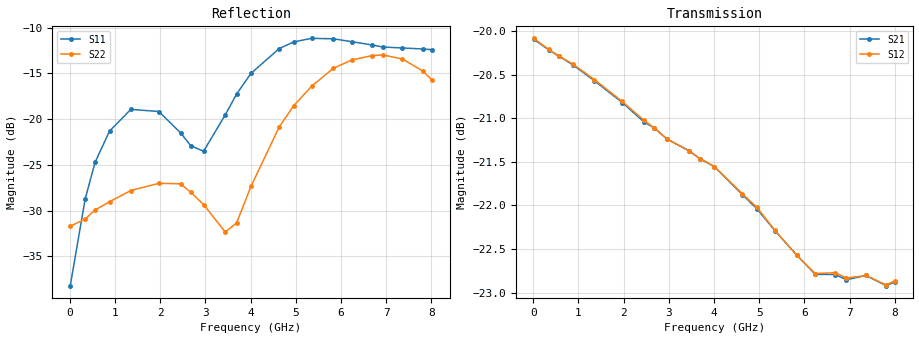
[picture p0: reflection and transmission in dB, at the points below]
!Agilent Technologies,E5071B,MY42404982,A.09.10
!Date: Mon Oct 20 13:36:23 2025
!Data & Calibration Information:
!Freq	S11:SOLT2(ON)	S21:SOLT2(ON)	S12:SOLT2(ON)	S22:SOLT2(ON)
# Hz S RI R 50
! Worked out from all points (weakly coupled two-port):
!   801 points, 10 MHz to 8.01 GHz, reference 50 ohm
!   highest |S21| = -20.09 dB at 10 MHz (marker M1); lowest = -22.9 dB at 7.81 GHz (marker M2)
!   lowest |S11| = -38.2 dB at 10 MHz (marker M3), VSWR 1.02, Z = 48.8 - j0.159 ohm
!   |S11| at or under -10 dB: start of sweep to end of sweep
!   |S22| runs from -32.4 to -13.0 dB; largest |S21 - S12| = 0.00077
!   S11 on the Smith chart (normalised r, x): 10 MHz: 0.98, -0.00; 4.63 GHz: 0.63, +0.13; 5.83 GHz: 1.18, +0.59; 6.93 GHz: 1.33, -0.49; 8.01 GHz: 0.63, -0.14
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1e7  -0.0122 -0.00163  0.0989 -0.00213  0.099 -0.00222  0.026 -0.000864
3.4e8  -0.0242 -0.0276  0.08 -0.0558  0.08 -0.0559  0.0225 -0.0174
5.6e8  -0.0433 -0.0389  0.0526 -0.0812  0.0525 -0.0813  0.0147 -0.0283
8.8e8  -0.0794 -0.0333  0.00115 -0.0956  0.00111 -0.0957  -0.0071 -0.0347
1.35e9  -0.1109 0.0218  -0.0678 -0.0646  -0.0679 -0.0647  -0.0368 -0.0175
1.97e9  -0.0507 0.0977  -0.0865 0.0282  -0.0866 0.0283  -0.0338 0.0291
2.45e9  0.0328 0.0775  -0.0372 0.0805  -0.0372 0.0807  -0.00152 0.0443
2.68e9  0.0594 0.0396  -0.00353 0.0879  -0.00349 0.0879  0.0146 0.037
2.96e9  0.0638 -0.0198  0.0366 0.0786  0.0366 0.0786  0.0267 0.0213
3.44e9  -0.00484 -0.1055  0.0811 0.0267  0.0811 0.0267  0.0183 -0.0158
3.69e9  -0.0691 -0.1183  0.084 -0.00892  0.084 -0.00918  -0.000574 -0.0271
4.01e9  -0.1553 -0.087  0.0663 -0.0509  0.0664 -0.0508  -0.0339 -0.0265
4.63e9  -0.2224 0.0966  -0.0117 -0.0797  -0.0116 -0.0798  -0.0803 0.0412
4.95e9  -0.172 0.2003  -0.0503 -0.061  -0.0503 -0.0612  -0.071 0.0944
5.35e9  -0.0391 0.2734  -0.0752 -0.0156  -0.0752 -0.0158  -0.0152 0.1505
5.83e9  0.1465 0.2325  -0.0616 0.0417  -0.0615 0.0418  0.0939 0.1646
6.24e9  0.2465 0.0968  -0.022 0.0691  -0.0213 0.0694  0.1811 0.1074
6.68e9  0.2391 -0.0869  0.03 0.066  0.0302 0.0661  0.2221 -0.00316
6.93e9  0.1773 -0.1728  0.0534 0.0483  0.0537 0.0482  0.2122 -0.0728
7.36e9  0.00957 -0.2446  0.0724 0.00116  0.0724 0.00111  0.1361 -0.1637
7.81e9  -0.1667 -0.175  0.053 -0.0479  0.0531 -0.0479  0.0134 -0.1825
8.01e9  -0.2145 -0.1068  0.0343 -0.0631  0.0345 -0.0631  -0.0344 -0.1603
